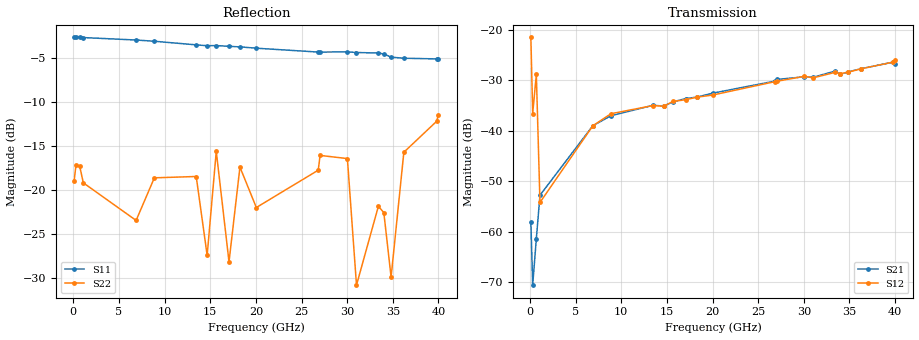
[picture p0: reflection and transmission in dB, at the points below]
!  2-Port S-parameters saved by WinCal
! VAR MeasName=S-Parameters (CALIBRATED_DATA) read from VNA (N5244A)
! VAR MeasDate=9/22/2011 5:01:19 PM
! VAR NAME=L8 2
! VAR FILENAME=L8 2.S2P
! VAR DATE=9/22/2011 5:01:19 PM
! VAR PHYS_PORTS=1,2
! VAR ObjTypeName=DATASET
! VAR IndexType=Frequency
# Hz S DB R 50
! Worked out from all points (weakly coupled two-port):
!   201 points, 100 MHz to 40 GHz, reference 50 ohm
!   highest |S21| = -26.35 dB at 39.8 GHz (marker M1); lowest = -70.5 dB at 299.5 MHz (marker M2)
!   lowest |S11| = -5.1 dB at 40 GHz (marker M3), VSWR 3.48, Z = 25.4 + j40.6 ohm
!   |S11| at or under -10 dB: nowhere
!   |S22| runs from -30.8 to -11.4 dB; largest |S21 - S12| = 0.086
!   S11 on the Smith chart (normalised r, x): 100 MHz: 0.15, +0.00; 8.878 GHz: 0.18, +0.15; 18.25 GHz: 0.23, +0.30; 27.03 GHz: 0.30, +0.45; 34.02 GHz: 0.37, +0.64; 40 GHz: 0.51, +0.81
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1e8  -2.62 179.7  -57.99 -156.2  -21.46 4.1  -18.91 4.2
2.995e8  -2.62 179.4  -70.54 12.0  -36.55 -2.0  -17.10 3.4
6.985e8  -2.63 178.4  -61.35 93.1  -28.79 76.9  -17.26 -12.5
1.0975e9  -2.64 177.6  -52.73 85.5  -54.16 106.0  -19.17 0.5
6.883e9  -2.92 165.6  -38.97 49.3  -38.98 51.9  -23.45 19.9
8.878e9  -3.06 162.0  -36.98 39.5  -36.58 40.0  -18.60 -8.8
1.34665e10  -3.47 153.7  -34.92 16.7  -34.97 16.8  -18.45 19.2
1.46635e10  -3.57 152.2  -35.06 10.5  -35.10 12.6  -27.42 71.8
1.5661e10  -3.55 150.1  -34.23 14.0  -34.15 13.3  -15.58 24.2
1.70575e10  -3.64 147.7  -33.58 3.3  -33.81 4.7  -28.16 22.5
1.82545e10  -3.70 145.2  -33.30 2.4  -33.32 3.0  -17.38 28.8
2.005e10  -3.85 141.5  -32.50 -7.7  -32.87 -5.4  -21.98 13.2
2.6833e10  -4.29 128.6  -30.12 -29.8  -30.23 -29.1  -17.73 -40.4
2.70325e10  -4.29 127.9  -29.80 -32.5  -30.16 -29.4  -16.05 -45.6
3.0025e10  -4.27 120.7  -29.27 -45.1  -29.18 -43.2  -16.41 -62.8
3.10225e10  -4.34 117.5  -29.36 -51.7  -29.47 -48.1  -30.81 -61.1
3.34165e10  -4.40 111.7  -28.14 -64.3  -28.40 -60.7  -21.85 179.2
3.4015e10  -4.51 109.3  -28.77 -66.4  -28.63 -64.5  -22.55 109.0
3.4813e10  -4.87 106.7  -28.31 -67.0  -28.38 -64.3  -29.90 138.6
3.62095e10  -4.99 104.0  -27.69 -78.7  -27.71 -76.5  -15.69 118.5
3.98005e10  -5.07 92.8  -26.35 -93.0  -26.35 -94.4  -12.17 84.8
4e10  -5.13 92.9  -26.68 -96.5  -26.01 -97.3  -11.40 89.1
